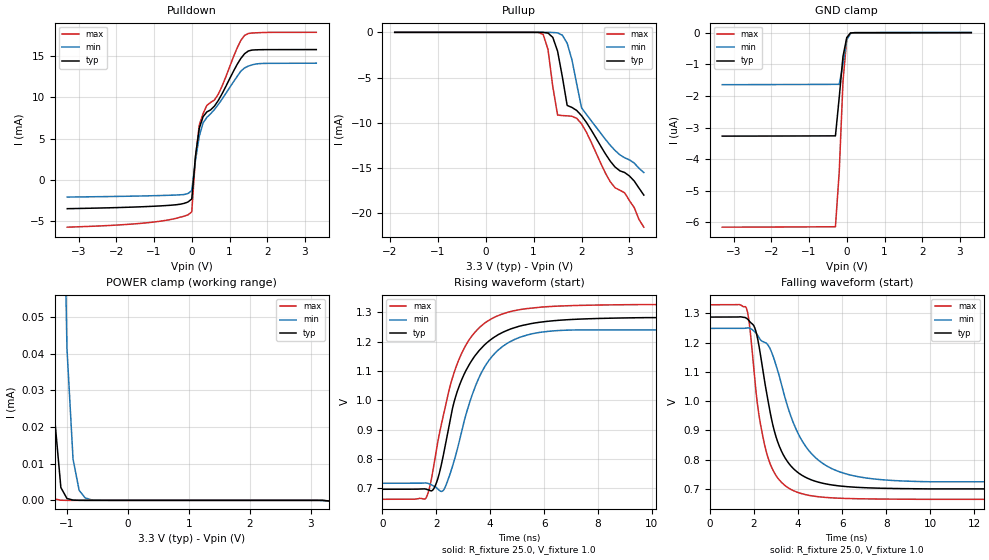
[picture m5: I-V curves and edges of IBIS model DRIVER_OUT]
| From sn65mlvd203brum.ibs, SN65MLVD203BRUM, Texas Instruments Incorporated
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[Model]   DRIVER_OUT
Model_type   3-state
|		 typ	 min	 max
C_comp 5.10247e-12	5.02357e-12	5.17192e-12
Vmeas  = 0.0V
[Temperature Range]		 27.0	 125.0	 -40.0
[Voltage range]		 3.3	 3.0	 3.6
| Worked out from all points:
|   slope of the pulldown table from 0 to 0.495 V, typ, clamps not added: 45.9 ohm
|   POWER clamp passes 1 mA (typ) near -1.46 V on its own axis
|   rising waveform, R_fixture 25.0, V_fixture 1.0: 20-80 % time 1.28ns typ, 1.2ns min, 1.2ns max; typ from 0.696 V to 1.28 V
|   falling waveform, R_fixture 25.0, V_fixture 1.0: 20-80 % time 1.05ns typ, 1.6ns min, 790ps max; typ from 1.29 V to 0.7 V
[GND_clamp]
|   Voltage   I(typ)   I(min)   I(max)
-3.3V     -3.271uA   -1.644uA   -6.151uA
-300mV    -3.263uA   -1.634uA   -6.138uA
-200mV    -2.051uA   -1.634uA   -4.407uA
-100mV    -747nA     -990.8nA   -1.541uA
0V        -155nA     -220.6nA   -183.5nA
100mV     -6.663nA   -26.08nA   -7.255nA
300mV     -11.24pA   5.787nA    -18.81pA
3.3V      620.2pA    12.61nA    334.5pA
[Power_clamp]
| Note that the[POWER_clamp]voltage table is referenced to Vcc
| and is calculated using Vtable=Vcc - Vmeasured.
|   Voltage   I(typ)   I(min)   I(max)
-1.9V     13.58mA    17.07mA    11.27mA
-1.5V     1.382mA    4.031mA    310.2uA
-1.4V     435.4uA    2.111mA    45.34uA
-1.3V     110.2uA    944.9uA    4.445uA
-1.2V     22.01uA    370.5uA    373.6nA
-1.1V     3.498uA    131.6uA    31.22nA
-1V       511.2nA    41.46uA    3.003nA
-900mV    74.19nA    11.22uA    670.2pA
-800mV    11.4nA     2.742uA    480.8pA
-700mV    2.366nA    650.5nA    456.3pA
-400mV    801pA      19.07nA    401.6pA
3.3V      -155nA     -220.6nA   -183.5nA
[Pulldown]
|   Voltage   I(typ)   I(min)   I(max)
-3.3V     -3.503mA   -2.095mA   -5.743mA
-1.2V     -3.248mA   -1.951mA   -5.217mA
-100mV    -2.692mA   -1.669mA   -4.252mA
0V        -2.327mA   -1.308mA   -3.885mA
100mV     2.911mA    2.418mA    2.786mA
200mV     6.249mA    5.285mA    6.655mA
300mV     7.642mA    6.899mA    8.017mA
400mV     8.224mA    7.56mA     9.022mA
700mV     9.585mA    9.103mA    10.34mA
1.3V      14.7mA     13.16mA    16.88mA
1.6V      15.72mA    13.93mA    17.78mA
3.3V      15.78mA    14.13mA    17.87mA
[Pullup]
|   Voltage   I(typ)   I(min)   I(max)
| Note that the[Pullup]voltage table is referenced to Vcc
| and is calculated using Vtable=Vcc - Vmeasured.
-1.9V     11.71uA    2.229uA    11.68uA
1.2V      3.69uA     731.6nA    -237.1uA
1.3V      -70.04uA   188.6nA    -1.89mA
1.4V      -548.9uA   -5.209uA   -6.016mA
1.5V      -2.075mA   -49.85uA   -9.153mA
1.6V      -4.928mA   -305.2uA   -9.211mA
1.7V      -8.088mA   -1.199mA   -9.239mA
1.8V      -8.309mA   -3.031mA   -9.29mA
2V        -9.219mA   -8.342mA   -10.12mA
2.6V      -14.26mA   -12.5mA    -16.55mA
2.9V      -15.52mA   -13.89mA   -17.77mA
3.3V      -18.02mA   -15.52mA   -21.57mA
[Ramp]
|   typ   min   max
dV/dt_r 0.351449/1.28325e-09 0.31383/1.19853e-09 0.398684/1.19531e-09
dV/dt_f 0.352473/7.53198e-10 0.314643/1.05222e-09 0.399146/6.27265e-10
R_load = 25ohm | Note: Measurement is single ended with 25ohm to ground
[Rising Waveform]
R_fixture = 25.0
V_fixture = 1.0
V_fixture_min = 1.00
V_fixture_max = 0.99
C_fixture = 0p
L_fixture = 0n
|   V(typ)   V(min)   V(max)
0s        696.3mV    716.8mV    662.2mV
1.62ns    696.8mV    718mV      666.4mV
1.93ns    701.7mV    706.6mV    788.6mV
2.26ns    810.4mV    692.3mV    946.1mV
2.87ns    1.053V     865mV      1.145V
3.32ns    1.136V     1.015V     1.219V
3.82ns    1.191V     1.117V     1.265V
5.51ns    1.261V     1.226V     1.314V
9.89ns    1.282V     1.24V      1.327V
9.99us    1.282V     1.24V      1.327V
[Falling Waveform]
R_fixture = 25.0
V_fixture = 1.0
V_fixture_min = 1.00
V_fixture_max = 0.99
C_fixture = 0p
L_fixture = 0n
|   V(typ)   V(min)   V(max)
0s        1.287V     1.248V     1.329V
1.66ns    1.283V     1.25V      1.318V
2.08ns    1.241V     1.234V     1.043V
2.45ns    1.084V     1.202V     862.4mV
2.89ns    908.5mV    1.149V     760mV
3.35ns    813.9mV    1.028V     715mV
4.15ns    747.6mV    868.5mV    683.7mV
5.25ns    716.9mV    780.5mV    670.5mV
9.98ns    699.7mV    724.1mV    664mV
9.99us    699.7mV    724.1mV    664mV
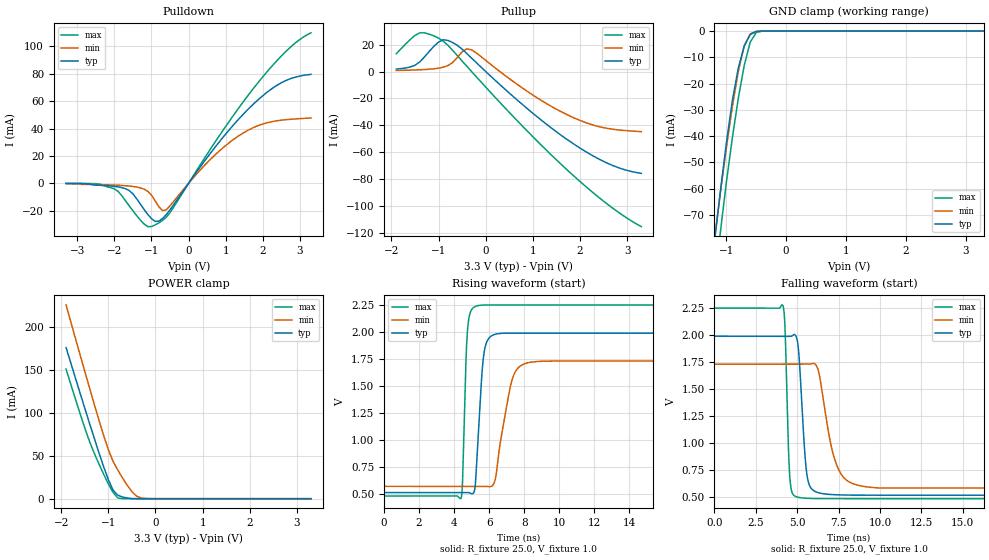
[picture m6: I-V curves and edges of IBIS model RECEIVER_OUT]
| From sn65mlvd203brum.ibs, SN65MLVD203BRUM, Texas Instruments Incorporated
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[Model]   RECEIVER_OUT
Model_type   3-state
Vmeas = 1.5V
Cref = 0pF
Vref = 0
|		 typ	 min	 max
C_comp 4.24381e-12	4.20818e-12	4.30916e-12
[Temperature Range]		 27.0	 125.0	 -40.0
[Voltage range]		 3.3	 3.0	 3.6
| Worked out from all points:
|   slope of the pulldown table from 0 to 0.495 V, typ, clamps not added: 26.6 ohm
|   slope of the pullup table from 0 to 0.495 V, typ, clamps not added: 31.3 ohm
|   GND clamp passes 1 mA (typ) near -0.57 V on its own axis
|   POWER clamp passes 1 mA (typ) near -0.62 V on its own axis
|   rising waveform, R_fixture 25.0, V_fixture 1.0: 20-80 % time 337ps typ, 724ps min, 197ps max; typ from 0.516 V to 1.99 V
|   falling waveform, R_fixture 25.0, V_fixture 1.0: 20-80 % time 352ps typ, 866ps min, 198ps max; typ from 1.99 V to 0.516 V
[GND_clamp]
|   Voltage   I(typ)   I(min)   I(max)
-3.3V     -24.22A    -7.599A    -36.71A
-1.2V     -80.86mA   -79.82mA   -98.17mA
-1.1V     -61.22mA   -61.74mA   -76.74mA
-1V       -42.83mA   -44.66mA   -57.78mA
-900mV    -26.59mA   -28.98mA   -40.85mA
-800mV    -14.12mA   -15.44mA   -25.67mA
-700mV    -5.709mA   -5.557mA   -13.05mA
-600mV    -1.346mA   -1.088mA   -4.193mA
-500mV    -159.9uA   -150.4uA   -573.8uA
-400mV    -11.19uA   -15.78uA   -32.55uA
3.3V      291.8pA    2.919uA    106pA
[Power_clamp]
| Note that the[POWER_clamp]voltage table is referenced to Vcc
| and is calculated using Vtable=Vcc - Vmeasured.
|   Voltage   I(typ)   I(min)   I(max)
-1.895V   176.3mA    226mA      151.2mA
-1.597V   122.9mA    167.5mA    98.96mA
-1.398V   87.8mA     129.1mA    66.67mA
-1.099V   37.29mA    73.71mA    28.52mA
-998.9mV  22.15mA    57.13mA    17.25mA
-899.2mV  9.985mA    43.61mA    7.301mA
-799.3mV  4.078mA    33.45mA    883.6uA
-599.5mV  715.1uA    15.72mA    355nA
-399.7mV  12.32uA    2.972mA    191.7pA
-299.8mV  715.1nA    813uA      127.8pA
-99.92mV  1.113nA    25.37uA    112.6pA
3.298V    -96.04pA   -3.059nA   -18.57pA
[Pulldown]
|   Voltage   I(typ)   I(min)   I(max)
-3.3V     -46.27uA   -102.5uA   -40.24uA
-2.4V     -1.389mA   -917.1uA   -482.7uA
-2V       -2.186mA   -1.244mA   -3.998mA
-1.7V     -3.884mA   -1.696mA   -12.62mA
-1.5V     -7.604mA   -2.235mA   -19.94mA
-1.1V     -22.57mA   -5.747mA   -31.54mA
-800mV    -27.56mA   -17.04mA   -28.84mA
-600mV    -22.84mA   -19.28mA   -24.66mA
700mV     25.86mA    20.4mA     29.54mA
1.7V      56.62mA    40.1mA     67.58mA
2.5V      73.41mA    46.11mA    92.93mA
3.3V      79.56mA    47.71mA    109.9mA
[Pullup]
|   Voltage   I(typ)   I(min)   I(max)
| Note that the[Pullup]voltage table is referenced to Vcc
| and is calculated using Vtable=Vcc - Vmeasured.
-1.895V   1.824mA    797.3uA    13.16mA
-1.597V   3.388mA    1.034mA    23.88mA
-1.398V   7.141mA    1.288mA    28.69mA
-998.9mV  21.88mA    2.493mA    24.74mA
-799.3mV  23.04mA    4.458mA    19.37mA
-499.6mV  16.55mA    14.66mA    7.786mA
-399.7mV  13.29mA    16.84mA    3.888mA
-299.8mV  9.949mA    16.04mA    -124fA
799.4mV   -25.08mA   -12.76mA   -41.21mA
1.699V    -49.75mA   -31.56mA   -72.05mA
2.598V    -68.27mA   -42.3mA    -98.83mA
3.298V    -75.53mA   -44.6mA    -115mA
[Ramp]
|   typ   min   max
dV/dt_r 0.884844/3.36631e-10 0.695301/7.23667e-10 1.06059/1.97166e-10
dV/dt_f 0.884635/3.1223e-10 0.689002/7.51669e-10 1.06057/1.7954e-10
R_load = 25ohm | Note: Measurement is single ended with 25ohm to ground
[Rising Waveform]
R_fixture = 25.0
V_fixture = 1.0
V_fixture_min = 1.00
V_fixture_max = 0.99
C_fixture = 0p
L_fixture = 0n
|   V(typ)   V(min)   V(max)
0s        515.8mV    573.2mV    483.7mV
4.39ns    515.8mV    573.2mV    461.6mV
4.7ns     516mV      573.2mV    1.84V
4.83ns    516.1mV    573.2mV    2.118V
5.19ns    560.7mV    573.2mV    2.236V
5.64ns    1.72V      573.4mV    2.25V
6.04ns    1.954V     569.5mV    2.252V
7.45ns    1.991V     1.62V      2.251V
9.62ns    1.991V     1.732V     2.251V
9.99us    1.99V      1.732V     2.251V
[Falling Waveform]
R_fixture = 25.0
V_fixture = 1.0
V_fixture_min = 1.00
V_fixture_max = 0.99
C_fixture = 0p
L_fixture = 0n
|   V(typ)   V(min)   V(max)
0s        1.99V      1.731V     2.252V
4.13ns    1.99V      1.731V     2.276V
4.27ns    1.99V      1.731V     2.05V
4.52ns    1.99V      1.731V     774.3mV
4.68ns    1.992V     1.731V     546.5mV
5.06ns    1.897V     1.731V     496.8mV
5.69ns    630.6mV    1.73V      486.8mV
6.28ns    539.5mV    1.67V      484.8mV
7.55ns    519.1mV    738.6mV    484.1mV
9.99us    516.1mV    582.8mV    483.9mV
